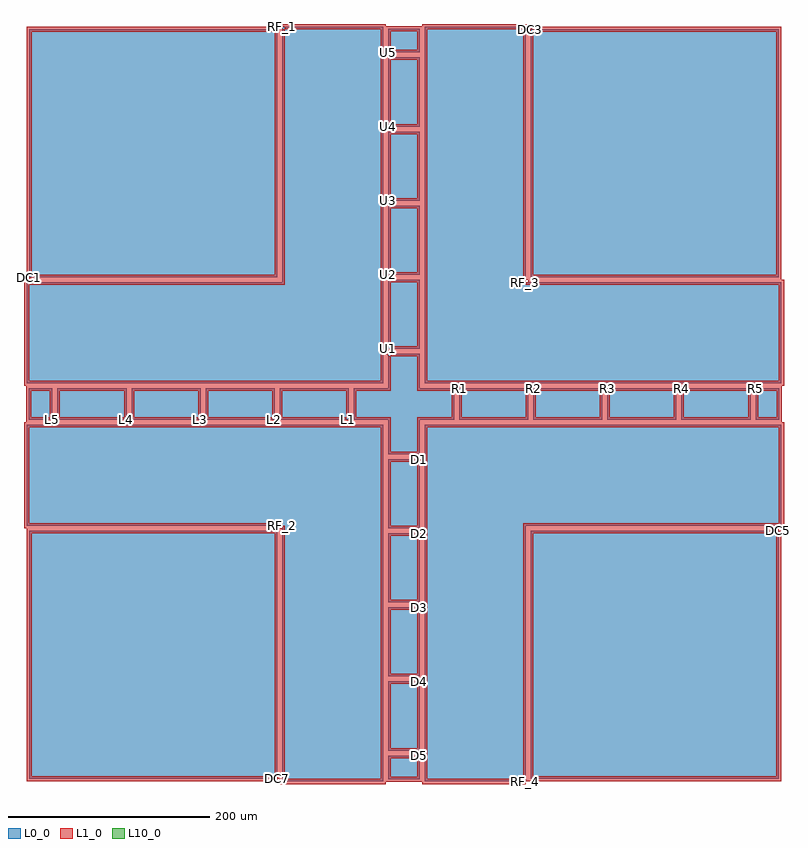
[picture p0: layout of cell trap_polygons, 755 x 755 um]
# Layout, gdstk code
import gdstk
lib = gdstk.Library(unit=1e-6, precision=1e-09)
def P(c, l, *ps):  # polygons
    for p in ps: c.add(gdstk.Polygon(p, *l))
L0_0 = (0, 0)
L1_0 = (1, 0)
L10_0 = (10, 0)

trap_polygons = lib.new_cell('trap_polygons')
P(trap_polygons, L0_0, [(-125.75,-372.5),(-372.5,-372.5),(-372.5,-125.75),(-125.75,-125.75),(-125.75,-372.5)],
  [(372.5,-125.75),(372.5,-372.5),(125.75,-372.5),(125.75,-125.75),(372.5,-125.75)],
  [(125.75,372.5),(372.5,372.5),(372.5,125.75),(125.75,125.75),(125.75,372.5)],
  [(-372.5,125.75),(-372.5,372.5),(-125.75,372.5),(-125.75,125.75),(-372.5,125.75)],
  [(-15.75,349.25),(-15.75,373),(15.75,373),(15.75,349.25),(-15.75,349.25)],
  [(349.25,15.75),(373,15.75),(373,-15.75),(349.25,-15.75),(349.25,15.75)],
  [(15.75,-349.25),(15.75,-373),(-15.75,-373),(-15.75,-349.25),(15.75,-349.25)],
  [(-349.25,-15.75),(-373,-15.75),(-373,15.75),(-349.25,15.75),(-349.25,-15.75)],
  [(-15.75,275.65),(-15.75,344.25),(15.75,344.25),(15.75,275.65),(-15.75,275.65)],
  [(275.65,15.75),(344.25,15.75),(344.25,-15.75),(275.65,-15.75),(275.65,15.75)],
  [(15.75,-275.65),(15.75,-344.25),(-15.75,-344.25),(-15.75,-275.65),(15.75,-275.65)],
  [(-275.65,-15.75),(-344.25,-15.75),(-344.25,15.75),(-275.65,15.75),(-275.65,-15.75)],
  [(-15.75,202.05),(-15.75,270.65),(15.75,270.65),(15.75,202.05),(-15.75,202.05)],
  [(202.05,15.75),(270.65,15.75),(270.65,-15.75),(202.05,-15.75),(202.05,15.75)],
  [(15.75,-202.05),(15.75,-270.65),(-15.75,-270.65),(-15.75,-202.05),(15.75,-202.05)],
  [(-202.05,-15.75),(-270.65,-15.75),(-270.65,15.75),(-202.05,15.75),(-202.05,-15.75)],
  [(-15.75,128.45),(-15.75,197.05),(15.75,197.05),(15.75,128.45),(-15.75,128.45)],
  [(128.45,15.75),(197.05,15.75),(197.05,-15.75),(128.45,-15.75),(128.45,15.75)],
  [(15.75,-128.45),(15.75,-197.05),(-15.75,-197.05),(-15.75,-128.45),(15.75,-128.45)],
  [(-128.45,-15.75),(-197.05,-15.75),(-197.05,15.75),(-128.45,15.75),(-128.45,-15.75)],
  [(-15.75,54.85),(-15.75,123.45),(15.75,123.45),(15.75,54.85),(-15.75,54.85)],
  [(54.85,15.75),(123.45,15.75),(123.45,-15.75),(54.85,-15.75),(54.85,15.75)],
  [(15.75,-54.85),(15.75,-123.45),(-15.75,-123.45),(-15.75,-54.85),(15.75,-54.85)],
  [(-54.85,-15.75),(-123.45,-15.75),(-123.45,15.75),(-54.85,15.75),(-54.85,-15.75)],
  [(-15.75,49.85),(15.75,49.85),(15.75,15.75),(49.85,15.75),(49.85,-15.75),(15.75,-15.75),(15.75,-49.85),(-15.75,-49.85),(-15.75,-15.75),(-49.85,-15.75),(-49.85,15.75),(-15.75,15.75),(-15.75,49.85)],
  [(120.75,-375),(20.75,-375),(20.75,-20.75),(375,-20.75),(375,-120.75),(120.75,-120.75),(120.75,-375)],
  [(120.75,120.75),(375,120.75),(375,20.75),(20.75,20.75),(20.75,375),(120.75,375),(120.75,120.75)],
  [(-120.75,-120.75),(-375,-120.75),(-375,-20.75),(-20.75,-20.75),(-20.75,-375),(-120.75,-375),(-120.75,-120.75)],
  [(-120.75,375),(-20.75,375),(-20.75,20.75),(-375,20.75),(-375,120.75),(-120.75,120.75),(-120.75,375)])
P(trap_polygons, L1_0, [(-125.75,-375),(-125.75,-370),(-370,-370),(-370,-128.25),(-128.25,-128.25),(-128.25,-372.5),(-123.25,-372.5),(-123.25,-123.25),(-375,-123.25),(-375,-375)],
  [(375,-125.75),(370,-125.75),(370,-370),(128.25,-370),(128.25,-128.25),(372.5,-128.25),(372.5,-123.25),(123.25,-123.25),(123.25,-375),(375,-375)],
  [(125.75,375),(125.75,370),(370,370),(370,128.25),(128.25,128.25),(128.25,372.5),(123.25,372.5),(123.25,123.25),(375,123.25),(375,375)],
  [(-375,125.75),(-370,125.75),(-370,370),(-128.25,370),(-128.25,128.25),(-372.5,128.25),(-372.5,123.25),(-123.25,123.25),(-123.25,375),(-375,375)],
  [(-18.25,349.25),(-13.25,349.25),(-13.25,370.5),(13.25,370.5),(13.25,351.75),(-15.75,351.75),(-15.75,346.75),(18.25,346.75),(18.25,375.5),(-18.25,375.5)],
  [(349.25,18.25),(349.25,13.25),(370.5,13.25),(370.5,-13.25),(351.75,-13.25),(351.75,15.75),(346.75,15.75),(346.75,-18.25),(375.5,-18.25),(375.5,18.25)],
  [(18.25,-349.25),(13.25,-349.25),(13.25,-370.5),(-13.25,-370.5),(-13.25,-351.75),(15.75,-351.75),(15.75,-346.75),(-18.25,-346.75),(-18.25,-375.5),(18.25,-375.5)],
  [(-349.25,-18.25),(-349.25,-13.25),(-370.5,-13.25),(-370.5,13.25),(-351.75,13.25),(-351.75,-15.75),(-346.75,-15.75),(-346.75,18.25),(-375.5,18.25),(-375.5,-18.25)],
  [(-18.25,275.65),(-13.25,275.65),(-13.25,341.75),(13.25,341.75),(13.25,278.15),(-15.75,278.15),(-15.75,273.15),(18.25,273.15),(18.25,346.75),(-18.25,346.75)],
  [(275.65,18.25),(275.65,13.25),(341.75,13.25),(341.75,-13.25),(278.15,-13.25),(278.15,15.75),(273.15,15.75),(273.15,-18.25),(346.75,-18.25),(346.75,18.25)],
  [(18.25,-275.65),(13.25,-275.65),(13.25,-341.75),(-13.25,-341.75),(-13.25,-278.15),(15.75,-278.15),(15.75,-273.15),(-18.25,-273.15),(-18.25,-346.75),(18.25,-346.75)],
  [(-275.65,-18.25),(-275.65,-13.25),(-341.75,-13.25),(-341.75,13.25),(-278.15,13.25),(-278.15,-15.75),(-273.15,-15.75),(-273.15,18.25),(-346.75,18.25),(-346.75,-18.25)],
  [(-18.25,202.05),(-13.25,202.05),(-13.25,268.15),(13.25,268.15),(13.25,204.55),(-15.75,204.55),(-15.75,199.55),(18.25,199.55),(18.25,273.15),(-18.25,273.15)],
  [(202.05,18.25),(202.05,13.25),(268.15,13.25),(268.15,-13.25),(204.55,-13.25),(204.55,15.75),(199.55,15.75),(199.55,-18.25),(273.15,-18.25),(273.15,18.25)],
  [(18.25,-202.05),(13.25,-202.05),(13.25,-268.15),(-13.25,-268.15),(-13.25,-204.55),(15.75,-204.55),(15.75,-199.55),(-18.25,-199.55),(-18.25,-273.15),(18.25,-273.15)],
  [(-202.05,-18.25),(-202.05,-13.25),(-268.15,-13.25),(-268.15,13.25),(-204.55,13.25),(-204.55,-15.75),(-199.55,-15.75),(-199.55,18.25),(-273.15,18.25),(-273.15,-18.25)],
  [(-18.25,128.45),(-13.25,128.45),(-13.25,194.55),(13.25,194.55),(13.25,130.95),(-15.75,130.95),(-15.75,125.95),(18.25,125.95),(18.25,199.55),(-18.25,199.55)],
  [(128.45,18.25),(128.45,13.25),(194.55,13.25),(194.55,-13.25),(130.95,-13.25),(130.95,15.75),(125.95,15.75),(125.95,-18.25),(199.55,-18.25),(199.55,18.25)],
  [(18.25,-128.45),(13.25,-128.45),(13.25,-194.55),(-13.25,-194.55),(-13.25,-130.95),(15.75,-130.95),(15.75,-125.95),(-18.25,-125.95),(-18.25,-199.55),(18.25,-199.55)],
  [(-128.45,-18.25),(-128.45,-13.25),(-194.55,-13.25),(-194.55,13.25),(-130.95,13.25),(-130.95,-15.75),(-125.95,-15.75),(-125.95,18.25),(-199.55,18.25),(-199.55,-18.25)],
  [(-18.25,54.85),(-13.25,54.85),(-13.25,120.95),(13.25,120.95),(13.25,57.35),(-15.75,57.35),(-15.75,52.35),(18.25,52.35),(18.25,125.95),(-18.25,125.95)],
  [(54.85,18.25),(54.85,13.25),(120.95,13.25),(120.95,-13.25),(57.35,-13.25),(57.35,15.75),(52.35,15.75),(52.35,-18.25),(125.95,-18.25),(125.95,18.25)],
  [(18.25,-54.85),(13.25,-54.85),(13.25,-120.95),(-13.25,-120.95),(-13.25,-57.35),(15.75,-57.35),(15.75,-52.35),(-18.25,-52.35),(-18.25,-125.95),(18.25,-125.95)],
  [(-54.85,-18.25),(-54.85,-13.25),(-120.95,-13.25),(-120.95,13.25),(-57.35,13.25),(-57.35,-15.75),(-52.35,-15.75),(-52.35,18.25),(-125.95,18.25),(-125.95,-18.25)],
  [(-15.75,52.35),(-15.75,47.35),(13.25,47.35),(13.25,13.25),(13.25,13.25),(47.35,13.25),(47.35,-13.25),(13.25,-13.25),(13.25,-13.25),(13.25,-47.35),(-13.25,-47.35),(-13.25,-13.25),(-13.25,-13.25),(-47.35,-13.25),(-47.35,13.25),(-13.25,13.25),(-13.25,13.25),(-13.25,49.85),(-18.25,49.85),(-18.25,18.25),(-52.35,18.25),(-52.35,18.25),(-52.35,-18.25),(-52.35,-18.25),(-18.25,-18.25),(-18.25,-52.35),(-18.25,-52.35),(18.25,-52.35),(18.25,-52.35),(18.25,-18.25),(52.35,-18.25),(52.35,-18.25),(52.35,18.25),(52.35,18.25),(18.25,18.25),(18.25,52.35),(18.25,52.35)],
  [(120.75,-377.5),(120.75,-372.5),(23.25,-372.5),(23.25,-23.25),(372.5,-23.25),(372.5,-118.25),(118.25,-118.25),(118.25,-375),(123.25,-375),(123.25,-123.25),(377.5,-123.25),(377.5,-18.25),(18.25,-18.25),(18.25,-377.5)],
  [(120.75,123.25),(120.75,118.25),(372.5,118.25),(372.5,23.25),(23.25,23.25),(23.25,372.5),(118.25,372.5),(118.25,120.75),(123.25,120.75),(123.25,377.5),(18.25,377.5),(18.25,18.25),(377.5,18.25),(377.5,123.25)],
  [(-120.75,-123.25),(-120.75,-118.25),(-372.5,-118.25),(-372.5,-23.25),(-23.25,-23.25),(-23.25,-372.5),(-118.25,-372.5),(-118.25,-120.75),(-123.25,-120.75),(-123.25,-377.5),(-18.25,-377.5),(-18.25,-18.25),(-377.5,-18.25),(-377.5,-123.25)],
  [(-120.75,377.5),(-120.75,372.5),(-23.25,372.5),(-23.25,23.25),(-372.5,23.25),(-372.5,118.25),(-118.25,118.25),(-118.25,375),(-123.25,375),(-123.25,123.25),(-377.5,123.25),(-377.5,18.25),(-18.25,18.25),(-18.25,377.5)])
P(trap_polygons, L10_0, [(0,0),(0,0),(0,0),(0,0)])
trap_polygons.add(gdstk.Label('DC7', (-125.75,-372.5), layer=2, texttype=0))
trap_polygons.add(gdstk.Label('DC5', (372.5,-125.75), layer=2, texttype=0))
trap_polygons.add(gdstk.Label('DC3', (125.75,372.5), layer=2, texttype=0))
trap_polygons.add(gdstk.Label('DC1', (-372.5,125.75), layer=2, texttype=0))
trap_polygons.add(gdstk.Label('U5', (-15.75,349.25), layer=2, texttype=0))
trap_polygons.add(gdstk.Label('R5', (349.25,15.75), layer=2, texttype=0))
trap_polygons.add(gdstk.Label('D5', (15.75,-349.25), layer=2, texttype=0))
trap_polygons.add(gdstk.Label('L5', (-349.25,-15.75), layer=2, texttype=0))
trap_polygons.add(gdstk.Label('U4', (-15.75,275.65), layer=2, texttype=0))
trap_polygons.add(gdstk.Label('R4', (275.65,15.75), layer=2, texttype=0))
trap_polygons.add(gdstk.Label('D4', (15.75,-275.65), layer=2, texttype=0))
trap_polygons.add(gdstk.Label('L4', (-275.65,-15.75), layer=2, texttype=0))
trap_polygons.add(gdstk.Label('U3', (-15.75,202.05), layer=2, texttype=0))
trap_polygons.add(gdstk.Label('R3', (202.05,15.75), layer=2, texttype=0))
trap_polygons.add(gdstk.Label('D3', (15.75,-202.05), layer=2, texttype=0))
trap_polygons.add(gdstk.Label('L3', (-202.05,-15.75), layer=2, texttype=0))
trap_polygons.add(gdstk.Label('U2', (-15.75,128.45), layer=2, texttype=0))
trap_polygons.add(gdstk.Label('R2', (128.45,15.75), layer=2, texttype=0))
trap_polygons.add(gdstk.Label('D2', (15.75,-128.45), layer=2, texttype=0))
trap_polygons.add(gdstk.Label('L2', (-128.45,-15.75), layer=2, texttype=0))
trap_polygons.add(gdstk.Label('U1', (-15.75,54.85), layer=2, texttype=0))
trap_polygons.add(gdstk.Label('R1', (54.85,15.75), layer=2, texttype=0))
trap_polygons.add(gdstk.Label('D1', (15.75,-54.85), layer=2, texttype=0))
trap_polygons.add(gdstk.Label('L1', (-54.85,-15.75), layer=2, texttype=0))
trap_polygons.add(gdstk.Label('C', (-15.75,49.85), layer=2, texttype=0))
trap_polygons.add(gdstk.Label('RF_4', (120.75,-375), layer=2, texttype=0))
trap_polygons.add(gdstk.Label('RF_3', (120.75,120.75), layer=2, texttype=0))
trap_polygons.add(gdstk.Label('RF_2', (-120.75,-120.75), layer=2, texttype=0))
trap_polygons.add(gdstk.Label('RF_1', (-120.75,375), layer=2, texttype=0))

lib.write_gds('trap_polygons.gds')
